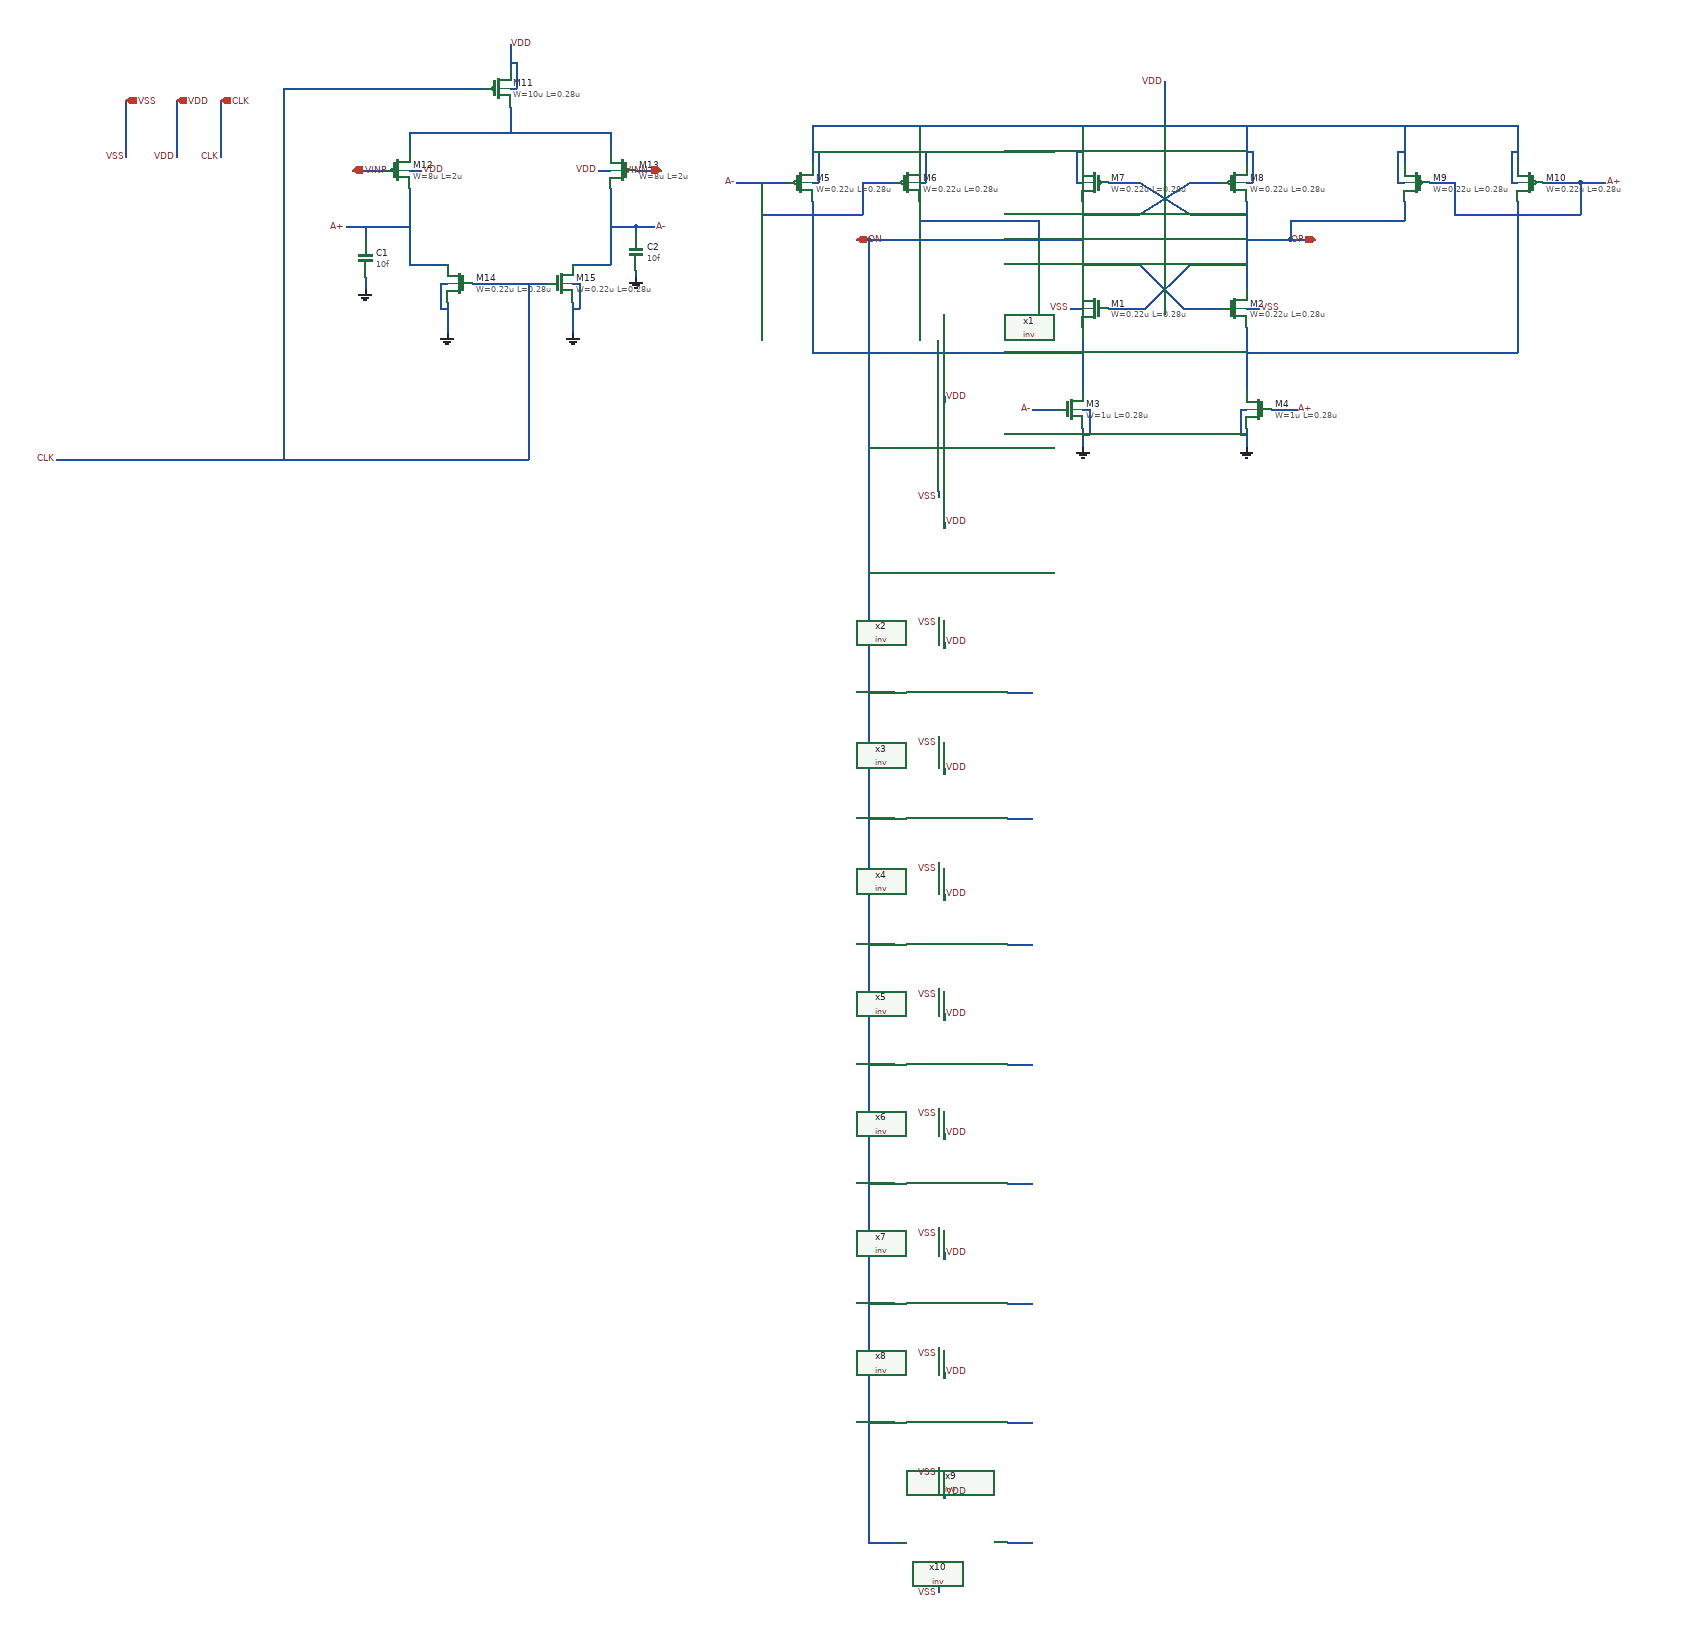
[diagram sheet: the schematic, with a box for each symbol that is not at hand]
v {xschem version=3.4.8RC file_version=1.3}
G {}
K {}
V {}
S {}
F {}
E {}
P 4 1 860 -2820 {}
P 4 1 1650 -2770 {}
N 2250 -2410 2250 -2380 {lab=GND}
N 2510 -2410 2510 -2380 {lab=GND}
N 2550 -2440 2590 -2440 {lab=A+}
N 2170 -2440 2210 -2440 {lab=A-}
N 2250 -2570 2250 -2470 {lab=#net1}
N 2510 -2570 2510 -2470 {lab=#net2}
N 2250 -2770 2250 -2630 {lab=ON}
N 2510 -2770 2510 -2630 {lab=OP}
N 2290 -2600 2350 -2600 {lab=OP}
N 2350 -2600 2420 -2670 {lab=OP}
N 2420 -2670 2510 -2670 {lab=OP}
N 2410 -2600 2470 -2600 {lab=ON}
N 2340 -2670 2410 -2600 {lab=ON}
N 2250 -2670 2340 -2670 {lab=ON}
N 2290 -2800 2340 -2800 {lab=OP}
N 2340 -2800 2420 -2750 {lab=OP}
N 2420 -2750 2510 -2750 {lab=OP}
N 2420 -2800 2470 -2800 {lab=ON}
N 2340 -2750 2420 -2800 {lab=ON}
N 2250 -2750 2340 -2750 {lab=ON}
N 2510 -2530 2940 -2530 {lab=#net2}
N 2940 -2770 2940 -2530 {lab=#net2}
N 2140 -2710 2250 -2710 {lab=ON}
N 1990 -2770 1990 -2740 {lab=ON}
N 1990 -2740 2180 -2740 {lab=ON}
N 2180 -2740 2180 -2710 {lab=ON}
N 2760 -2770 2760 -2740 {lab=OP}
N 2580 -2740 2760 -2740 {lab=OP}
N 2580 -2740 2580 -2710 {lab=OP}
N 2510 -2710 2580 -2710 {lab=OP}
N 2580 -2710 2620 -2710 {lab=OP}
N 1820 -2770 1820 -2530 {lab=#net1}
N 1820 -2530 2250 -2530 {lab=#net1}
N 1820 -2890 1820 -2830 {lab=VDD}
N 1990 -2890 1990 -2830 {lab=VDD}
N 2250 -2890 2250 -2830 {lab=VDD}
N 2510 -2890 2510 -2830 {lab=VDD}
N 2760 -2890 2760 -2830 {lab=VDD}
N 2940 -2890 2940 -2830 {lab=VDD}
N 2980 -2800 3040 -2800 {lab=A+}
N 2800 -2800 2840 -2800 {lab=A+}
N 2840 -2800 2840 -2750 {lab=A+}
N 2840 -2750 3040 -2750 {lab=A+}
N 3040 -2800 3040 -2750 {lab=A+}
N 1820 -2890 2940 -2890 {lab=VDD}
N 3040 -2800 3080 -2800 {lab=A+}
N 1900 -2800 1950 -2800 {lab=A-}
N 1900 -2800 1900 -2750 {lab=A-}
N 1740 -2750 1900 -2750 {lab=A-}
N 1740 -2800 1740 -2750 {lab=A-}
N 1700 -2800 1780 -2800 {lab=A-}
N 2380 -2960 2380 -2890 {lab=VDD}
N 2500 -2440 2510 -2440 {lab=GND}
N 2500 -2440 2500 -2400 {lab=GND}
N 2500 -2400 2510 -2400 {lab=GND}
N 2250 -2440 2260 -2440 {lab=GND}
N 2260 -2440 2260 -2400 {lab=GND}
N 2250 -2400 2260 -2400 {lab=GND}
N 2510 -2600 2530 -2600 {lab=VSS}
N 2230 -2600 2250 -2600 {lab=VSS}
N 1820 -2800 1830 -2800 {lab=VDD}
N 1830 -2850 1830 -2800 {lab=VDD}
N 1820 -2850 1830 -2850 {lab=VDD}
N 1990 -2800 2000 -2800 {lab=VDD}
N 2000 -2850 2000 -2800 {lab=VDD}
N 1990 -2850 2000 -2850 {lab=VDD}
N 2240 -2800 2250 -2800 {lab=VDD}
N 2240 -2850 2240 -2800 {lab=VDD}
N 2240 -2850 2250 -2850 {lab=VDD}
N 2510 -2800 2520 -2800 {lab=VDD}
N 2520 -2850 2520 -2800 {lab=VDD}
N 2510 -2850 2520 -2850 {lab=VDD}
N 2750 -2800 2760 -2800 {lab=VDD}
N 2750 -2850 2750 -2800 {lab=VDD}
N 2750 -2850 2760 -2850 {lab=VDD}
N 2930 -2800 2940 -2800 {lab=VDD}
N 2930 -2850 2930 -2800 {lab=VDD}
N 2930 -2850 2940 -2850 {lab=VDD}
N 1440 -2670 1500 -2670 {lab=A-}
N 1500 -2790 1500 -2670 {lab=A-}
N 1190 -2670 1240 -2670 {lab=A+}
N 1180 -2670 1190 -2670 {lab=A+}
N 1180 -2790 1180 -2670 {lab=A+}
N 1280 -2640 1400 -2640 {lab=CLK}
N 1180 -2880 1180 -2850 {lab=#net3}
N 1180 -2880 1500 -2880 {lab=#net3}
N 1500 -2880 1500 -2850 {lab=#net3}
N 1340 -2920 1340 -2880 {lab=#net3}
N 1240 -2950 1300 -2950 {lab=CLK}
N 1340 -3020 1340 -2980 {lab=VDD}
N 1240 -2610 1240 -2560 {lab=GND}
N 1440 -2610 1440 -2560 {lab=GND}
N 1540 -2820 1580 -2820 {lab=VINN}
N 1090 -2820 1140 -2820 {lab=VINP}
N 1140 -2730 1180 -2730 {lab=A+}
N 1500 -2730 1540 -2730 {lab=A-}
N 1440 -2640 1450 -2640 {lab=GND}
N 1450 -2640 1450 -2600 {lab=GND}
N 1440 -2600 1450 -2600 {lab=GND}
N 1230 -2640 1240 -2640 {lab=GND}
N 1230 -2640 1230 -2600 {lab=GND}
N 1230 -2600 1240 -2600 {lab=GND}
N 1340 -2950 1350 -2950 {lab=VDD}
N 1350 -2990 1350 -2950 {lab=VDD}
N 1340 -2990 1350 -2990 {lab=VDD}
N 1180 -2820 1200 -2820 {lab=VDD}
N 1480 -2820 1500 -2820 {lab=VDD}
N 810 -2930 810 -2840 {lab=VDD}
N 880 -2930 880 -2840 {lab=CLK}
N 620 -2360 670 -2360 {lab=CLK}
N 1370 -2640 1370 -2370 {lab=CLK}
N 930 -2360 1370 -2360 {lab=CLK}
N 1370 -2370 1370 -2360 {lab=CLK}
N 980 -2950 980 -2360 {lab=CLK}
N 980 -2950 1240 -2950 {lab=CLK}
N 730 -2930 730 -2840 {lab=VSS}
N 850 -2360 930 -2360 {lab=CLK}
N 670 -2360 850 -2360 {lab=CLK}
N 1910 -2710 2140 -2710 {lab=ON}
N 1910 -1210 1950 -1210 {lab=ON}
N 1910 -1400 1950 -1400 {lab=ON}
N 1910 -1590 1950 -1590 {lab=ON}
N 1910 -1790 1950 -1790 {lab=ON}
N 1910 -1990 1950 -1990 {lab=ON}
N 1910 -2180 1950 -2180 {lab=ON}
N 1910 -2380 1950 -2380 {lab=ON}
N 1890 -2710 1910 -2710 {lab=ON}
N 1910 -640 1950 -640 {lab=ON}
N 1910 -830 1950 -830 {lab=ON}
N 1910 -1020 1950 -1020 {lab=ON}
N 2130 -2380 2170 -2380 {lab=#net4}
N 2130 -2180 2170 -2180 {lab=#net5}
N 2130 -1990 2170 -1990 {lab=#net6}
N 2130 -1790 2170 -1790 {lab=#net7}
N 2130 -1590 2170 -1590 {lab=#net8}
N 2130 -1400 2170 -1400 {lab=#net9}
N 2130 -1210 2170 -1210 {lab=#net10}
N 2130 -1020 2170 -1020 {lab=#net11}
N 2130 -830 2170 -830 {lab=#net12}
N 2130 -640 2170 -640 {lab=#net13}
N 2030 -2460 2030 -2450 {lab=VDD}
N 2020 -2310 2020 -2300 {lab=VSS}
N 2030 -2260 2030 -2250 {lab=VDD}
N 2020 -2110 2020 -2100 {lab=VSS}
N 2030 -2070 2030 -2060 {lab=VDD}
N 2020 -1920 2020 -1910 {lab=VSS}
N 2030 -1870 2030 -1860 {lab=VDD}
N 2020 -1720 2020 -1710 {lab=VSS}
N 2030 -1670 2030 -1660 {lab=VDD}
N 2020 -1520 2020 -1510 {lab=VSS}
N 2030 -1480 2030 -1470 {lab=VDD}
N 2020 -1330 2020 -1320 {lab=VSS}
N 2030 -1290 2030 -1280 {lab=VDD}
N 2020 -1140 2020 -1130 {lab=VSS}
N 2030 -1100 2030 -1090 {lab=VDD}
N 2020 -950 2020 -940 {lab=VSS}
N 2030 -910 2030 -900 {lab=VDD}
N 2020 -760 2020 -750 {lab=VSS}
N 2030 -720 2030 -710 {lab=VDD}
N 2020 -570 2020 -560 {lab=VSS}
N 1080 -2730 1140 -2730 {lab=A+}
N 1110 -2730 1110 -2710 {lab=A+}
N 1540 -2730 1570 -2730 {lab=A-}
N 1540 -2730 1540 -2720 {lab=A-}
N 1110 -2650 1110 -2630 {lab=GND}
N 1540 -2660 1540 -2650 {lab=GND}
N 1910 -2400 1910 -640 {lab=ON}
N 1910 -2710 1910 -2400 {lab=ON}
C {symbols/nfet_03v3.sym} 2270 -2600 0 1 {name=M1
L=0.28u
W=0.22u
nf=1
m=1
ad="'int((nf+1)/2) * W/nf * 0.18u'"
pd="'2*int((nf+1)/2) * (W/nf + 0.18u)'"
as="'int((nf+2)/2) * W/nf * 0.18u'"
ps="'2*int((nf+2)/2) * (W/nf + 0.18u)'"
nrd="'0.18u / W'" nrs="'0.18u / W'"
sa=0 sb=0 sd=0
model=nfet_03v3
spiceprefix=X
}
C {symbols/nfet_03v3.sym} 2490 -2600 0 0 {name=M2
L=0.28u
W=0.22u
nf=1
m=1
ad="'int((nf+1)/2) * W/nf * 0.18u'"
pd="'2*int((nf+1)/2) * (W/nf + 0.18u)'"
as="'int((nf+2)/2) * W/nf * 0.18u'"
ps="'2*int((nf+2)/2) * (W/nf + 0.18u)'"
nrd="'0.18u / W'" nrs="'0.18u / W'"
sa=0 sb=0 sd=0
model=nfet_03v3
spiceprefix=X
}
C {symbols/nfet_03v3.sym} 2230 -2440 0 0 {name=M3
L=0.28u
W=1u
nf=1
m=1
ad="'int((nf+1)/2) * W/nf * 0.18u'"
pd="'2*int((nf+1)/2) * (W/nf + 0.18u)'"
as="'int((nf+2)/2) * W/nf * 0.18u'"
ps="'2*int((nf+2)/2) * (W/nf + 0.18u)'"
nrd="'0.18u / W'" nrs="'0.18u / W'"
sa=0 sb=0 sd=0
model=nfet_03v3
spiceprefix=X
}
C {symbols/nfet_03v3.sym} 2530 -2440 0 1 {name=M4
L=0.28u
W=1u
nf=1
m=1
ad="'int((nf+1)/2) * W/nf * 0.18u'"
pd="'2*int((nf+1)/2) * (W/nf + 0.18u)'"
as="'int((nf+2)/2) * W/nf * 0.18u'"
ps="'2*int((nf+2)/2) * (W/nf + 0.18u)'"
nrd="'0.18u / W'" nrs="'0.18u / W'"
sa=0 sb=0 sd=0
model=nfet_03v3
spiceprefix=X
}
C {symbols/pfet_03v3.sym} 1800 -2800 0 0 {name=M5
L=0.28u
W=0.22u
nf=1
m=1
ad="'int((nf+1)/2) * W/nf * 0.18u'"
pd="'2*int((nf+1)/2) * (W/nf + 0.18u)'"
as="'int((nf+2)/2) * W/nf * 0.18u'"
ps="'2*int((nf+2)/2) * (W/nf + 0.18u)'"
nrd="'0.18u / W'" nrs="'0.18u / W'"
sa=0 sb=0 sd=0
model=pfet_03v3
spiceprefix=X
}
C {symbols/pfet_03v3.sym} 1970 -2800 0 0 {name=M6
L=0.28u
W=0.22u
nf=1
m=1
ad="'int((nf+1)/2) * W/nf * 0.18u'"
pd="'2*int((nf+1)/2) * (W/nf + 0.18u)'"
as="'int((nf+2)/2) * W/nf * 0.18u'"
ps="'2*int((nf+2)/2) * (W/nf + 0.18u)'"
nrd="'0.18u / W'" nrs="'0.18u / W'"
sa=0 sb=0 sd=0
model=pfet_03v3
spiceprefix=X
}
C {symbols/pfet_03v3.sym} 2270 -2800 0 1 {name=M7
L=0.28u
W=0.22u
nf=1
m=1
ad="'int((nf+1)/2) * W/nf * 0.18u'"
pd="'2*int((nf+1)/2) * (W/nf + 0.18u)'"
as="'int((nf+2)/2) * W/nf * 0.18u'"
ps="'2*int((nf+2)/2) * (W/nf + 0.18u)'"
nrd="'0.18u / W'" nrs="'0.18u / W'"
sa=0 sb=0 sd=0
model=pfet_03v3
spiceprefix=X
}
C {symbols/pfet_03v3.sym} 2490 -2800 0 0 {name=M8
L=0.28u
W=0.22u
nf=1
m=1
ad="'int((nf+1)/2) * W/nf * 0.18u'"
pd="'2*int((nf+1)/2) * (W/nf + 0.18u)'"
as="'int((nf+2)/2) * W/nf * 0.18u'"
ps="'2*int((nf+2)/2) * (W/nf + 0.18u)'"
nrd="'0.18u / W'" nrs="'0.18u / W'"
sa=0 sb=0 sd=0
model=pfet_03v3
spiceprefix=X
}
C {symbols/pfet_03v3.sym} 2780 -2800 0 1 {name=M9
L=0.28u
W=0.22u
nf=1
m=1
ad="'int((nf+1)/2) * W/nf * 0.18u'"
pd="'2*int((nf+1)/2) * (W/nf + 0.18u)'"
as="'int((nf+2)/2) * W/nf * 0.18u'"
ps="'2*int((nf+2)/2) * (W/nf + 0.18u)'"
nrd="'0.18u / W'" nrs="'0.18u / W'"
sa=0 sb=0 sd=0
model=pfet_03v3
spiceprefix=X
}
C {symbols/pfet_03v3.sym} 2960 -2800 0 1 {name=M10
L=0.28u
W=0.22u
nf=1
m=1
ad="'int((nf+1)/2) * W/nf * 0.18u'"
pd="'2*int((nf+1)/2) * (W/nf + 0.18u)'"
as="'int((nf+2)/2) * W/nf * 0.18u'"
ps="'2*int((nf+2)/2) * (W/nf + 0.18u)'"
nrd="'0.18u / W'" nrs="'0.18u / W'"
sa=0 sb=0 sd=0
model=pfet_03v3
spiceprefix=X
}
C {iopin.sym} 1890 -2710 0 1 {name=p4 lab=ON}
C {iopin.sym} 2620 -2710 0 0 {name=p5 lab=OP}
C {lab_wire.sym} 2170 -2440 0 0 {name=p6 sig_type=std_logic lab=A-}
C {lab_wire.sym} 2590 -2440 0 1 {name=p7 sig_type=std_logic lab=A+}
C {lab_wire.sym} 3080 -2800 0 1 {name=p9 sig_type=std_logic lab=A+}
C {gnd.sym} 2510 -2380 0 0 {name=l3 lab=GND}
C {gnd.sym} 2250 -2380 0 0 {name=l4 lab=GND}
C {lab_wire.sym} 1700 -2800 0 0 {name=p11 sig_type=std_logic lab=A-}
C {symbols/pfet_03v3.sym} 1320 -2950 0 0 {name=M11
L=0.28u
W=10u
nf=1
m=1
ad="'int((nf+1)/2) * W/nf * 0.18u'"
pd="'2*int((nf+1)/2) * (W/nf + 0.18u)'"
as="'int((nf+2)/2) * W/nf * 0.18u'"
ps="'2*int((nf+2)/2) * (W/nf + 0.18u)'"
nrd="'0.18u / W'" nrs="'0.18u / W'"
sa=0 sb=0 sd=0
model=pfet_03v3
spiceprefix=X
}
C {symbols/pfet_03v3.sym} 1160 -2820 0 0 {name=M12
L=2u
W=8u
nf=1
m=1
ad="'int((nf+1)/2) * W/nf * 0.18u'"
pd="'2*int((nf+1)/2) * (W/nf + 0.18u)'"
as="'int((nf+2)/2) * W/nf * 0.18u'"
ps="'2*int((nf+2)/2) * (W/nf + 0.18u)'"
nrd="'0.18u / W'" nrs="'0.18u / W'"
sa=0 sb=0 sd=0
model=pfet_03v3
spiceprefix=X
}
C {symbols/pfet_03v3.sym} 1520 -2820 0 1 {name=M13
L=2u
W=8u
nf=1
m=1
ad="'int((nf+1)/2) * W/nf * 0.18u'"
pd="'2*int((nf+1)/2) * (W/nf + 0.18u)'"
as="'int((nf+2)/2) * W/nf * 0.18u'"
ps="'2*int((nf+2)/2) * (W/nf + 0.18u)'"
nrd="'0.18u / W'" nrs="'0.18u / W'"
sa=0 sb=0 sd=0
model=pfet_03v3
spiceprefix=X
}
C {symbols/nfet_03v3.sym} 1260 -2640 0 1 {name=M14
L=0.28u
W=0.22u
nf=1
m=1
ad="'int((nf+1)/2) * W/nf * 0.18u'"
pd="'2*int((nf+1)/2) * (W/nf + 0.18u)'"
as="'int((nf+2)/2) * W/nf * 0.18u'"
ps="'2*int((nf+2)/2) * (W/nf + 0.18u)'"
nrd="'0.18u / W'" nrs="'0.18u / W'"
sa=0 sb=0 sd=0
model=nfet_03v3
spiceprefix=X
}
C {symbols/nfet_03v3.sym} 1420 -2640 0 0 {name=M15
L=0.28u
W=0.22u
nf=1
m=1
ad="'int((nf+1)/2) * W/nf * 0.18u'"
pd="'2*int((nf+1)/2) * (W/nf + 0.18u)'"
as="'int((nf+2)/2) * W/nf * 0.18u'"
ps="'2*int((nf+2)/2) * (W/nf + 0.18u)'"
nrd="'0.18u / W'" nrs="'0.18u / W'"
sa=0 sb=0 sd=0
model=nfet_03v3
spiceprefix=X
}
C {gnd.sym} 1240 -2560 0 0 {name=l6 lab=GND}
C {gnd.sym} 1440 -2560 0 0 {name=l7 lab=GND}
C {iopin.sym} 1580 -2820 0 0 {name=p14 lab=VINN}
C {iopin.sym} 1090 -2820 0 1 {name=p15 lab=VINP}
C {iopin.sym} 810 -2930 0 1 {name=p16 lab=VDD}
C {lab_wire.sym} 1480 -2820 0 0 {name=p17 sig_type=std_logic lab=VDD}
C {lab_wire.sym} 1200 -2820 0 1 {name=p19 sig_type=std_logic lab=VDD}
C {lab_wire.sym} 1340 -3020 0 1 {name=p20 sig_type=std_logic lab=VDD}
C {iopin.sym} 880 -2930 0 1 {name=p21 lab=CLK}
C {lab_wire.sym} 2380 -2960 0 0 {name=p22 sig_type=std_logic lab=VDD}
C {lab_wire.sym} 880 -2840 0 0 {name=p24 sig_type=std_logic lab=CLK}
C {lab_wire.sym} 810 -2840 0 0 {name=p3 sig_type=std_logic lab=VDD}
C {lab_wire.sym} 1080 -2730 0 0 {name=p25 sig_type=std_logic lab=A+}
C {lab_wire.sym} 1570 -2730 0 1 {name=p26 sig_type=std_logic lab=A-}
C {lab_wire.sym} 620 -2360 0 0 {name=p1 sig_type=std_logic lab=CLK}
C {iopin.sym} 730 -2930 0 1 {name=p8 lab=VSS}
C {lab_wire.sym} 730 -2840 0 0 {name=p10 sig_type=std_logic lab=VSS}
C {lab_wire.sym} 2230 -2600 0 0 {name=p12 sig_type=std_logic lab=VSS}
C {lab_wire.sym} 2530 -2600 0 1 {name=p13 sig_type=std_logic lab=VSS}
C {inv.sym} 2160 -2280 0 0 {name=x1}
C {inv.sym} 2160 -2080 0 0 {name=x2}
C {inv.sym} 2160 -1890 0 0 {name=x3}
C {inv.sym} 2160 -1690 0 0 {name=x4}
C {inv.sym} 2160 -1490 0 0 {name=x5}
C {inv.sym} 2160 -1300 0 0 {name=x6}
C {inv.sym} 2160 -1110 0 0 {name=x7}
C {noconn.sym} 2170 -2380 0 1 {name=l1}
C {noconn.sym} 2170 -2180 0 1 {name=l2}
C {noconn.sym} 2170 -1990 0 1 {name=l5}
C {noconn.sym} 2170 -1790 0 1 {name=l8}
C {inv.sym} 2160 -920 0 0 {name=x8}
C {inv.sym} 2160 -730 0 0 {name=x9}
C {inv.sym} 2160 -540 0 0 {name=x10}
C {noconn.sym} 2170 -1590 0 1 {name=l9}
C {noconn.sym} 2170 -1400 0 1 {name=l10}
C {noconn.sym} 2170 -1210 0 1 {name=l11}
C {noconn.sym} 2170 -1020 0 1 {name=l12}
C {noconn.sym} 2170 -830 0 1 {name=l13}
C {noconn.sym} 2170 -640 0 1 {name=l14}
C {lab_wire.sym} 2030 -2460 0 1 {name=p2 sig_type=std_logic lab=VDD}
C {lab_wire.sym} 2030 -2260 0 1 {name=p18 sig_type=std_logic lab=VDD}
C {lab_wire.sym} 2030 -2070 0 1 {name=p23 sig_type=std_logic lab=VDD}
C {lab_wire.sym} 2030 -1870 0 1 {name=p27 sig_type=std_logic lab=VDD}
C {lab_wire.sym} 2030 -1670 0 1 {name=p28 sig_type=std_logic lab=VDD}
C {lab_wire.sym} 2030 -1480 0 1 {name=p29 sig_type=std_logic lab=VDD}
C {lab_wire.sym} 2030 -1290 0 1 {name=p30 sig_type=std_logic lab=VDD}
C {lab_wire.sym} 2030 -1100 0 1 {name=p31 sig_type=std_logic lab=VDD}
C {lab_wire.sym} 2030 -910 0 1 {name=p32 sig_type=std_logic lab=VDD}
C {lab_wire.sym} 2030 -720 0 1 {name=p33 sig_type=std_logic lab=VDD}
C {lab_wire.sym} 2020 -2300 3 0 {name=p34 sig_type=std_logic lab=VSS}
C {lab_wire.sym} 2020 -2100 3 0 {name=p35 sig_type=std_logic lab=VSS}
C {lab_wire.sym} 2020 -1910 3 0 {name=p36 sig_type=std_logic lab=VSS}
C {lab_wire.sym} 2020 -1710 3 0 {name=p37 sig_type=std_logic lab=VSS}
C {lab_wire.sym} 2020 -1510 3 0 {name=p38 sig_type=std_logic lab=VSS}
C {lab_wire.sym} 2020 -1320 3 0 {name=p39 sig_type=std_logic lab=VSS}
C {lab_wire.sym} 2020 -1130 3 0 {name=p40 sig_type=std_logic lab=VSS}
C {lab_wire.sym} 2020 -940 3 0 {name=p41 sig_type=std_logic lab=VSS}
C {lab_wire.sym} 2020 -750 3 0 {name=p42 sig_type=std_logic lab=VSS}
C {lab_wire.sym} 2020 -560 3 0 {name=p43 sig_type=std_logic lab=VSS}
C {capa.sym} 1110 -2680 0 0 {name=C1
m=1
value=10f
footprint=1206
device="ceramic capacitor"}
C {capa.sym} 1540 -2690 0 0 {name=C2
m=1
value=10f
footprint=1206
device="ceramic capacitor"}
C {gnd.sym} 1540 -2650 0 0 {name=l15 lab=GND}
C {gnd.sym} 1110 -2630 0 0 {name=l16 lab=GND}
